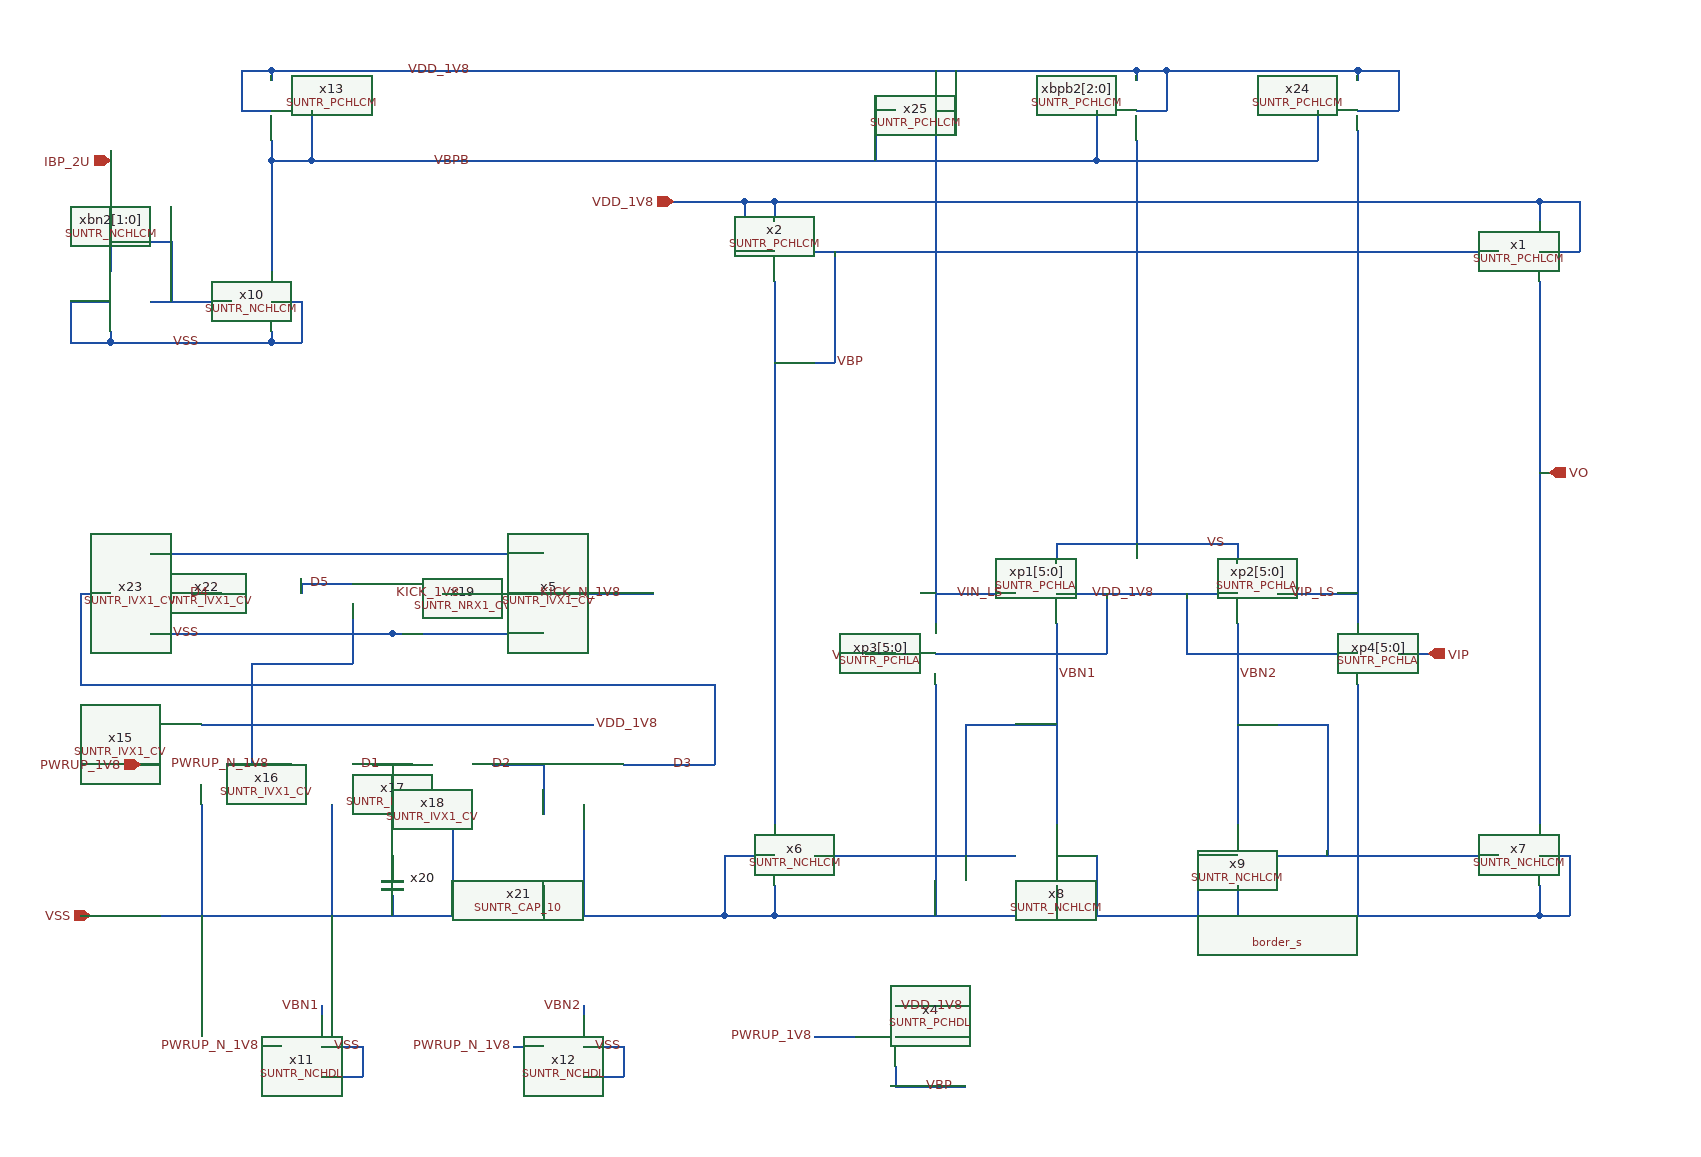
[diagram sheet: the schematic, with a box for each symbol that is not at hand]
v {xschem version=3.0.0 file_version=1.2 }
G {}
K {}
V {}
S {}
E {}
N 190 -810 190 -610 {
lab=VBN1}
N 370 -810 370 -610 {
lab=VBN2}
N 190 -550 190 -520 {
lab=VSS}
N 190 -520 670 -520 {
lab=VSS}
N 670 -550 670 -520 {
lab=VSS}
N 410 -580 630 -580 {
lab=VBN2}
N 370 -550 370 -520 {
lab=VSS}
N -90 -550 -90 -520 {
lab=VSS}
N -90 -520 190 -520 {
lab=VSS}
N -140 -580 -90 -580 {
lab=VSS}
N -140 -580 -140 -520 {
lab=VSS}
N -140 -520 -90 -520 {
lab=VSS}
N -50 -580 150 -580 {
lab=VBN1}
N 100 -710 190 -710 {
lab=VBN1}
N 100 -710 100 -580 {
lab=VBN1}
N 370 -710 460 -710 {
lab=VBN2}
N 460 -710 460 -580 {
lab=VBN2}
N -350 -390 -320 -390 {
lab=PWRUP_N_1V8}
N -600 -390 -580 -390 {
lab=PWRUP_N_1V8}
N 190 -890 190 -870 {
lab=VS}
N 190 -890 370 -890 {
lab=VS}
N 370 -890 370 -870 {
lab=VS}
N 190 -840 370 -840 {
lab=VDD_1V8}
N -90 -1150 -90 -610 {
lab=VBP}
N -50 -1180 630 -1180 {
lab=VBP}
N -90 -1230 -90 -1210 {
lab=VDD_1V8}
N -90 -1230 670 -1230 {
lab=VDD_1V8}
N 670 -1230 670 -1210 {
lab=VDD_1V8}
N 670 -1180 710 -1180 {
lab=VDD_1V8}
N 710 -1230 710 -1180 {
lab=VDD_1V8}
N 670 -1230 710 -1230 {
lab=VDD_1V8}
N -120 -1180 -90 -1180 {
lab=VDD_1V8}
N -120 -1230 -120 -1180 {
lab=VDD_1V8}
N -120 -1230 -90 -1230 {
lab=VDD_1V8}
N 670 -1150 670 -1130 {
lab=VO}
N 30 -400 100 -400 {
lab=VDD_1V8}
N 30 -430 100 -430 {
lab=VDD_1V8}
N 100 -430 100 -400 {
lab=VDD_1V8}
N 670 -1130 670 -610 {
lab=VO}
N -50 -400 -10 -400 {
lab=PWRUP_1V8}
N -190 -1230 -120 -1230 {
lab=VDD_1V8}
N -90 -1070 -30 -1070 {
lab=VBP}
N -30 -1180 -30 -1070 {
lab=VBP}
N 670 -960 680 -960 {
lab=VO}
N 670 -580 700 -580 {
lab=VSS}
N 700 -580 700 -520 {
lab=VSS}
N 330 -580 370 -580 {
lab=VSS}
N 330 -580 330 -520 {
lab=VSS}
N 190 -580 230 -580 {
lab=VSS}
N 230 -580 230 -520 {
lab=VSS}
N -780 -520 -140 -520 {
lab=VSS}
N -470 -880 -460 -880 {
lab=VDD_1V8}
N -470 -800 -460 -800 {
lab=VSS}
N -370 -670 -320 -670 {
lab=D2}
N -490 -670 -450 -670 {
lab=D1}
N -620 -670 -570 -670 {
lab=PWRUP_N_1V8}
N -280 -710 -270 -710 {
lab=VDD_1V8}
N -410 -710 -290 -710 {
lab=VDD_1V8}
N -530 -710 -410 -710 {
lab=VDD_1V8}
N -660 -710 -530 -710 {
lab=VDD_1V8}
N -320 -670 -320 -620 {
lab=D2}
N -470 -670 -470 -610 {
lab=D1}
N -470 -540 -470 -520 {
lab=VSS}
N -320 -550 -320 -520 {
lab=VSS}
N -410 -630 -410 -520 {
lab=VSS}
N -280 -630 -280 -520 {
lab=VSS}
N -530 -630 -530 -520 {
lab=VSS}
N -660 -630 -660 -520 {
lab=VSS}
N -730 -670 -700 -670 {
lab=PWRUP_1V8}
N -240 -670 -150 -670 {
lab=D3}
N -150 -750 -150 -670 {
lab=D3}
N -420 -750 -150 -750 {
lab=D3}
N -420 -840 -360 -840 {
lab=KICK_1V8}
N 120 -840 150 -840 {
lab=VIN_LS}
N -290 -710 -280 -710 {
lab=VDD_1V8}
N -600 -880 -470 -880 {
lab=VDD_1V8}
N -560 -850 -560 -840 {
lab=D5}
N -560 -850 -510 -850 {
lab=D5}
N -600 -800 -470 -800 {
lab=VSS}
N -500 -750 -420 -750 {
lab=D3}
N -510 -830 -510 -770 {
lab=PWRUP_N_1V8}
N -670 -840 -640 -840 {
lab=D4}
N -710 -880 -600 -880 {
lab=VDD_1V8}
N -710 -800 -600 -800 {
lab=VSS}
N -640 -750 -500 -750 {
lab=D3}
N -780 -840 -750 -840 {
lab=D3}
N -610 -770 -510 -770 {
lab=PWRUP_N_1V8}
N 270 -1000 270 -890 {
lab=VS}
N -780 -750 -640 -750 {
lab=D3}
N -780 -840 -780 -750 {
lab=D3}
N -610 -770 -610 -670 {
lab=PWRUP_N_1V8}
N -460 -880 -320 -880 {
lab=VDD_1V8}
N -470 -800 -320 -800 {
lab=VSS}
N -280 -840 -210 -840 {
lab=KICK_N_1V8}
N 670 -520 700 -520 {
lab=VSS}
N -540 -430 -540 -420 {
lab=VBN1}
N -280 -430 -280 -420 {
lab=VBN2}
N -540 -390 -500 -390 {
lab=VSS}
N -500 -390 -500 -360 {
lab=VSS}
N -540 -360 -500 -360 {
lab=VSS}
N -280 -390 -240 -390 {
lab=VSS}
N -240 -390 -240 -360 {
lab=VSS}
N -280 -360 -240 -360 {
lab=VSS}
N 30 -370 30 -350 {
lab=VBP}
N 30 -350 100 -350 {
lab=VBP}
N -750 -1280 -750 -1160 {
lab=IBP_2U}
N -790 -1130 -750 -1130 {
lab=VSS}
N -790 -1130 -790 -1090 {
lab=VSS}
N -790 -1090 -750 -1090 {
lab=VSS}
N -750 -1100 -750 -1090 {
lab=VSS}
N -710 -1130 -630 -1130 {
lab=IBP_2U}
N -750 -1090 -590 -1090 {
lab=VSS}
N -590 -1100 -590 -1090 {
lab=VSS}
N -590 -1130 -560 -1130 {
lab=VSS}
N -560 -1130 -560 -1090 {
lab=VSS}
N -590 -1090 -560 -1090 {
lab=VSS}
N -690 -1190 -690 -1130 {
lab=IBP_2U}
N -750 -1190 -690 -1190 {
lab=IBP_2U}
N -620 -1320 -590 -1320 {
lab=VDD_1V8}
N -620 -1360 -620 -1320 {
lab=VDD_1V8}
N -620 -1360 -590 -1360 {
lab=VDD_1V8}
N -590 -1360 -590 -1350 {
lab=VDD_1V8}
N 270 -1320 300 -1320 {
lab=VDD_1V8}
N 300 -1360 300 -1320 {
lab=VDD_1V8}
N 270 -1360 300 -1360 {
lab=VDD_1V8}
N 270 -1360 270 -1350 {
lab=VDD_1V8}
N -590 -1290 -590 -1270 {
lab=VBPB}
N -590 -1270 -550 -1270 {
lab=VBPB}
N -550 -1320 -550 -1270 {
lab=VBPB}
N -550 -1270 230 -1270 {
lab=VBPB}
N 230 -1320 230 -1270 {
lab=VBPB}
N -590 -1360 270 -1360 {
lab=VDD_1V8}
N 230 -1270 450 -1270 {
lab=VBPB}
N 450 -1320 450 -1270 {
lab=VBPB}
N 490 -1360 490 -1350 {
lab=VDD_1V8}
N 300 -1360 490 -1360 {
lab=VDD_1V8}
N 490 -1320 530 -1320 {
lab=VDD_1V8}
N 530 -1360 530 -1320 {
lab=VDD_1V8}
N 490 -1360 530 -1360 {
lab=VDD_1V8}
N 270 -1290 270 -1000 {
lab=VS}
N 70 -1360 70 -1350 {
lab=VDD_1V8}
N 70 -1320 90 -1320 {
lab=VDD_1V8}
N 90 -1360 90 -1320 {
lab=VDD_1V8}
N 10 -1320 30 -1320 {
lab=VBPB}
N 10 -1320 10 -1270 {
lab=VBPB}
N 0 -780 30 -780 {
lab=VIN}
N 70 -1300 70 -810 {
lab=VIN_LS}
N 70 -780 240 -780 {
lab=VDD_1V8}
N 240 -840 240 -780 {
lab=VDD_1V8}
N 70 -840 120 -840 {
lab=VIN_LS}
N 70 -750 70 -520 {
lab=VSS}
N 490 -1300 490 -810 {
lab=VIP_LS}
N 320 -780 490 -780 {
lab=VDD_1V8}
N 320 -840 320 -780 {
lab=VDD_1V8}
N 490 -750 490 -520 {
lab=VSS}
N 530 -780 560 -780 {
lab=VIP}
N 410 -840 490 -840 {
lab=VIP_LS}
N -590 -1270 -590 -1160 {
lab=VBPB}
C {cborder/border_s.sym} 400 -480 0 0 {}
C {SUN_TR_SKY130NM/SUNTR_PCHLCM.sym} 630 -1180 0 0 {name=x1 xoffset=0 yoffset=0 angle=0 M=1}
C {SUN_TR_SKY130NM/SUNTR_PCHLCM.sym} -50 -1180 0 1 {name=x2 xoffset=0 yoffset=0 angle=0 M=1}
C {SUN_TR_SKY130NM/SUNTR_PCHDL.sym} -10 -400 0 0 {name=x4 xoffset=0 yoffset=0 angle=0 M=1}
C {SUN_TR_SKY130NM/SUNTR_NCHLCM.sym} 630 -580 0 0 {name=x7 xoffset=0 yoffset=0 angle=0 M=1}
C {SUN_TR_SKY130NM/SUNTR_NCHLCM.sym} -50 -580 0 1 {name=x6 xoffset=0 yoffset=0 angle=0 M=1}
C {SUN_TR_SKY130NM/SUNTR_NCHLCM.sym} 150 -580 0 0 {name=x8 xoffset=0 yoffset=0 angle=0 M=1}
C {SUN_TR_SKY130NM/SUNTR_NCHLCM.sym} 410 -580 0 1 {name=x9 xoffset=0 yoffset=0 angle=0 M=1}
C {SUN_TR_SKY130NM/SUNTR_NCHDL.sym} -580 -390 0 0 {name=x11 xoffset=0 yoffset=0 angle=0 M=1}
C {SUN_TR_SKY130NM/SUNTR_NCHDL.sym} -320 -390 0 0 {name=x12 xoffset=0 yoffset=0 angle=0 M=1}
C {SUN_TR_SKY130NM/SUNTR_PCHLA.sym} 150 -840 0 0 {name=xp1[5:0] xoffset=0 yoffset=0 angle=0 M=100}
C {SUN_TR_SKY130NM/SUNTR_PCHLA.sym} 410 -840 0 1 {name=xp2[5:0] xoffset=0 yoffset=0 angle=0 M=100}
C {devices/ipin.sym} -190 -1230 0 0 {name=p1 lab=VDD_1V8}
C {devices/lab_pin.sym} -30 -1070 0 1 {name=l2 sig_type=std_logic lab=VBP}
C {devices/opin.sym} 680 -960 0 0 {name=p2 lab=VO}
C {devices/lab_pin.sym} -50 -400 0 0 {name=l5 sig_type=std_logic lab=PWRUP_1V8}
C {devices/lab_pin.sym} 190 -760 0 1 {name=l6 sig_type=std_logic lab=VBN1}
C {devices/lab_pin.sym} 370 -760 0 1 {name=l7 sig_type=std_logic lab=VBN2}
C {devices/ipin.sym} -770 -520 0 0 {name=p3 lab=VSS}
C {SUN_TR_SKY130NM/SUNTR_IVX1_CV.sym} -700 -670 0 0 {name=x15 xoffset=0 yoffset=0 angle=0 M=1}
C {SUN_TR_SKY130NM/SUNTR_IVX1_CV.sym} -570 -670 0 0 {name=x16 xoffset=0 yoffset=0 angle=0 M=1}
C {SUN_TR_SKY130NM/SUNTR_IVX1_CV.sym} -450 -670 0 0 {name=x17 xoffset=0 yoffset=0 angle=0 M=1}
C {SUN_TR_SKY130NM/SUNTR_IVX1_CV.sym} -320 -670 0 0 {name=x18 xoffset=0 yoffset=0 angle=0 M=1}
C {SUN_TR_SKY130NM/SUNTR_NRX1_CV.sym} -510 -830 0 0 {name=x19 xoffset=0 yoffset=0 angle=0 M=1}
C {devices/lab_pin.sym} -690 -880 3 1 {name=l8 sig_type=std_logic lab=VDD_1V8}
C {devices/lab_pin.sym} -660 -800 1 1 {name=l9 sig_type=std_logic lab=VSS}
C {devices/lab_pin.sym} -270 -710 0 1 {name=l10 sig_type=std_logic lab=VDD_1V8}
C {SUN_TR_SKY130NM/SUNTR_CAP_10.sym} -470 -550 0 0 {name=x20 xoffset=0 yoffset=0 angle=0 M=1}
C {SUN_TR_SKY130NM/SUNTR_CAP_10.sym} -320 -560 0 0 {name=x21 xoffset=0 yoffset=0 angle=0 M=1}
C {devices/ipin.sym} -720 -670 0 0 {name=p4 lab=PWRUP_1V8}
C {devices/lab_pin.sym} -400 -840 3 1 {name=l11 sig_type=std_logic lab=KICK_1V8}
C {devices/lab_pin.sym} -590 -670 1 1 {name=l12 sig_type=std_logic lab=PWRUP_N_1V8}
C {devices/ipin.sym} 10 -780 0 0 {name=p5 lab=VIN}
C {devices/ipin.sym} 560 -780 0 1 {name=p6 lab=VIP}
C {devices/lab_pin.sym} -480 -670 3 1 {name=l13 sig_type=std_logic lab=D1}
C {devices/lab_pin.sym} -350 -670 3 1 {name=l14 sig_type=std_logic lab=D2}
C {devices/lab_pin.sym} -170 -670 3 1 {name=l15 sig_type=std_logic lab=D3}
C {SUN_TR_SKY130NM/SUNTR_IVX1_CV.sym} -640 -840 0 0 {name=x22 xoffset=0 yoffset=0 angle=0 M=1}
C {devices/lab_pin.sym} -530 -850 3 1 {name=l16 sig_type=std_logic lab=D5}
C {SUN_TR_SKY130NM/SUNTR_IVX1_CV.sym} -750 -840 0 0 {name=x23 xoffset=0 yoffset=0 angle=0 M=1}
C {devices/lab_pin.sym} -650 -840 3 1 {name=l17 sig_type=std_logic lab=D4}
C {devices/ipin.sym} -750 -1270 1 0 {name=p7 lab=IBP_2U}
C {SUN_TR_SKY130NM/SUNTR_IVX1_CV.sym} -360 -840 0 0 {name=x5 xoffset=0 yoffset=0 angle=0 M=1}
C {devices/lab_pin.sym} -240 -840 3 1 {name=l1 sig_type=std_logic lab=KICK_N_1V8}
C {devices/lab_wire.sym} -500 -390 0 0 {name=l3 sig_type=std_logic lab=VSS}
C {devices/lab_wire.sym} -600 -390 0 0 {name=l4 sig_type=std_logic lab=PWRUP_N_1V8}
C {devices/lab_wire.sym} -350 -390 0 0 {name=l18 sig_type=std_logic lab=PWRUP_N_1V8}
C {devices/lab_wire.sym} -540 -430 0 0 {name=l19 sig_type=std_logic lab=VBN1}
C {devices/lab_wire.sym} -280 -430 0 0 {name=l20 sig_type=std_logic lab=VBN2}
C {devices/lab_wire.sym} -240 -390 0 0 {name=l21 sig_type=std_logic lab=VSS}
C {devices/lab_wire.sym} 100 -430 0 0 {name=l22 sig_type=std_logic lab=VDD_1V8}
C {devices/lab_wire.sym} 90 -350 0 0 {name=l23 sig_type=std_logic lab=VBP}
C {SUN_TR_SKY130NM/SUNTR_NCHLCM.sym} -710 -1130 0 1 {name=xbn2[1:0] xoffset=0 yoffset=0 angle=0 M=1}
C {SUN_TR_SKY130NM/SUNTR_NCHLCM.sym} -630 -1130 0 0 {name=x10 xoffset=0 yoffset=0 angle=0 M=1}
C {SUN_TR_SKY130NM/SUNTR_PCHLCM.sym} -550 -1320 0 1 {name=x13 xoffset=0 yoffset=0 angle=0 M=1}
C {SUN_TR_SKY130NM/SUNTR_PCHLCM.sym} 230 -1320 0 0 {name=xbpb2[2:0] xoffset=0 yoffset=0 angle=0 M=1}
C {SUN_TR_SKY130NM/SUNTR_PCHLCM.sym} 450 -1320 0 0 {name=x24 xoffset=0 yoffset=0 angle=0 M=1}
C {SUN_TR_SKY130NM/SUNTR_PCHLCM.sym} 30 -1320 0 0 {name=x25 xoffset=0 yoffset=0 angle=0 M=1}
C {SUN_TR_SKY130NM/SUNTR_PCHLA.sym} 30 -780 0 0 {name=xp3[5:0] xoffset=0 yoffset=0 angle=0 M=1}
C {devices/lab_wire.sym} 290 -840 0 0 {name=l24 sig_type=std_logic lab=VDD_1V8}
C {SUN_TR_SKY130NM/SUNTR_PCHLA.sym} 530 -780 0 1 {name=xp4[5:0] xoffset=0 yoffset=0 angle=0 M=1}
C {devices/lab_wire.sym} -390 -1360 0 0 {name=l25 sig_type=std_logic lab=VDD_1V8}
C {devices/lab_wire.sym} -660 -1090 0 0 {name=l26 sig_type=std_logic lab=VSS}
C {devices/lab_wire.sym} 140 -840 0 0 {name=l27 sig_type=std_logic lab=VIN_LS}
C {devices/lab_wire.sym} 470 -840 0 0 {name=l28 sig_type=std_logic lab=VIP_LS}
C {devices/lab_wire.sym} -390 -1270 0 0 {name=l29 sig_type=std_logic lab=VBPB}
C {devices/lab_wire.sym} 360 -890 0 0 {name=l30 sig_type=std_logic lab=VS}
